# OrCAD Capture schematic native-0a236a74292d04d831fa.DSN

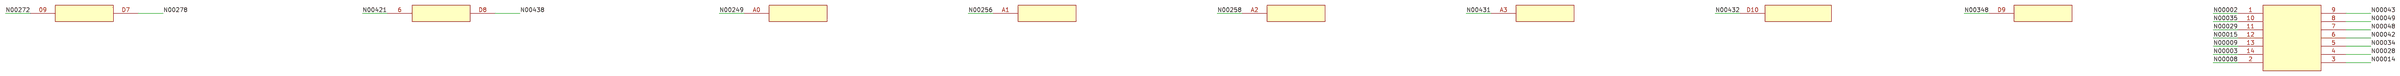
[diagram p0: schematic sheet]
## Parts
P1  CONNECTOR
P2  CONNECTOR
P3  CONNECTOR
P4  CONNECTOR
P26  CONNECTOR
P27  CONNECTOR
P28  CONNECTOR
P29  CONNECTOR
U6  XIA0-nRF52840-DIP

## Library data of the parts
P1 = OBS_P1
P2 = OBS_P2
P3 = OBS_P3
P4 = OBS_P4
P26 = OBS_P26
P27 = OBS_P27
P28 = OBS_P28
P29 = OBS_P29
U6 = OBS_U6

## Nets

Not connected (* = marked no-connect by the designer): P1 09 D7; P2 6 D8; P3 D10; P4 D9; P26 A0; P27 A1; P28 A2; P29 A3; U6 1 2 3 4 5 6 7 8 9 10 11 12 13 14
